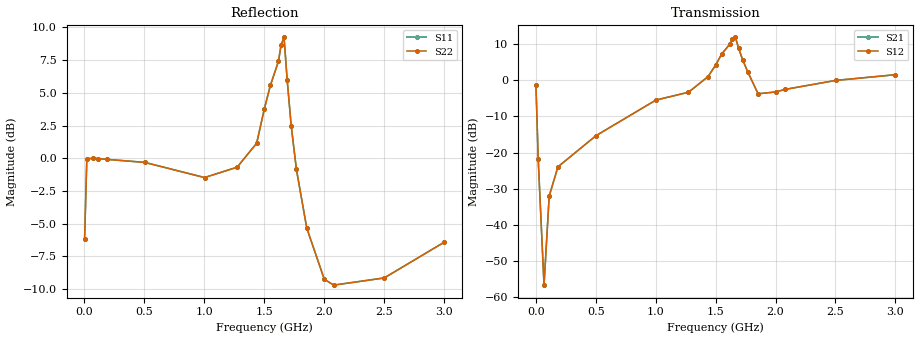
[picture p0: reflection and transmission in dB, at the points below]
!s-Parameter Generated by FASTRON Sdn. Bhd.
!FASTRON P/N : MICC-100X
!Keysight Technologies,E4991B,MY54100416,A.01.15
!Date: Fri Aug 28 11:05:22 2026
!Version  : Rev00 Fri Aug 28 11:05:22 2026
!Data & Calibration Information:
!PortZ  Port1:50+j0  Port2:50+j0
!When reading, reference impedance value at option line is always used.
! Remarks : This data is being provided solely for informational purposes.
!Freq	S11	S21	S12	S22
# Hz S dB R 50
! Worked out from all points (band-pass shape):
!   1601 points, 1 MHz to 3 GHz, reference 50 ohm
!   highest |S21| = 11.80 dB at 1.665 GHz (marker M1); lowest = -56.6 dB at 68.48 MHz (marker M2)
!   |S21| within 3 dB of the highest: 1.595 GHz to 1.692 GHz (96.87 MHz wide, 5.89 % of centre)
!   lowest |S11| = -9.7 dB at 2.08 GHz (marker M3), VSWR 1.98, Z = 80.7 - j31.6 ohm
!   |S11| at or under -10 dB: nowhere
!   |S22| runs from -9.7 to 9.2 dB; largest |S21 - S12| = 0
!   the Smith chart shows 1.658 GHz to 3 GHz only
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1000000  -6.20 59.6  -1.28 -29.3  -1.28 -29.3  -6.20 59.6
1.974375e7  -0.03 4.7  -21.70 -84.8  -21.70 -84.8  -0.03 4.7
6.84775e7  -0.01 0.0  -56.62 -10.3  -56.62 -10.3  -0.01 0.0
1.115881e8  -0.02 -1.4  -32.02 82.8  -32.02 82.8  -0.02 -1.4
1.846888e8  -0.08 -3.6  -23.95 79.7  -23.95 79.7  -0.08 -3.6
5.014581e8  -0.31 -9.7  -15.36 73.2  -15.36 73.2  -0.31 -9.7
1.001916e9  -1.47 -32.0  -5.52 57.6  -5.52 57.6  -1.47 -32.0
1.273701e9  -0.68 -41.1  -3.35 63.5  -3.35 63.5  -0.68 -41.1
1.436771e9  1.15 -62.5  0.96 65.0  0.96 65.0  1.15 -62.5
1.5005e9  3.76 -75.5  4.16 67.6  4.16 67.6  3.76 -75.5
1.551108e9  5.57 -99.8  7.20 54.7  7.20 54.7  5.57 -99.8
1.618586e9  7.41 -135.2  9.93 31.8  9.93 31.8  7.41 -135.2
1.641078e9  8.69 -156.4  11.27 17.3  11.27 17.3  8.69 -156.4
1.665445e9  9.24 171.0  11.80 -6.7  11.80 -6.7  9.24 171.0
1.691686e9  5.95 133.4  8.84 -31.4  8.84 -31.4  5.95 133.4
1.725425e9  2.45 109.7  5.62 -40.8  5.62 -40.8  2.45 109.7
1.768536e9  -0.85 85.7  2.27 -44.2  2.27 -44.2  -0.85 85.7
1.854757e9  -5.33 36.1  -3.78 -29.6  -3.78 -29.6  -5.33 36.1
2.000958e9  -9.24 -19.9  -3.27 9.9  -3.27 9.9  -9.24 -19.9
2.079682e9  -9.69 -32.2  -2.57 13.6  -2.57 13.6  -9.69 -32.2
2.501416e9  -9.14 -78.2  -0.09 20.2  -0.09 20.2  -9.14 -78.2
3e9  -6.42 -100.9  1.49 23.3  1.49 23.3  -6.42 -100.9
